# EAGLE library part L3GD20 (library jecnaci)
L3GD20 MEMS motion sensor - three-axis digital output gyroscope

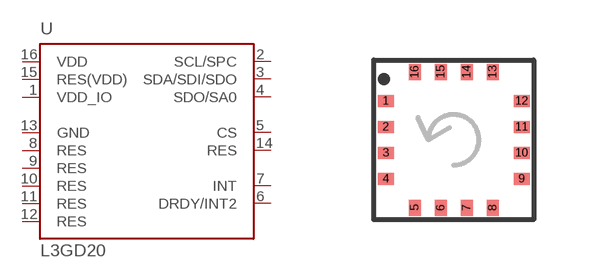
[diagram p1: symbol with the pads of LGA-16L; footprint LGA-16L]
Designator prefix U

## L3GD20  [LGA-16L]
1  VDD_IO  pwr
2  SCL/SPC  in
3  SDA/SDI/SDO
4  SDO/SA0  out
5  CS  in
6  DRDY/INT2
7  INT  out
8  RES  nc
9  RES  nc
10  RES  nc
11  RES  nc
12  RES  nc
13  GND  pwr
14  RES  nc
15  RES(VDD)  pwr
16  VDD  pwr

## Footprint LGA-16L (pad centres in mm)
smd 0.4 x 0.3: 1 -1.7,0.975; 2 -1.7,0.325; 3 -1.7,-0.325; 4 -1.7,-0.975; 9 1.7,-0.975; 10 1.7,-0.325; 11 1.7,0.325; 12 1.7,0.975
smd 0.3 x 0.4: 5 -0.975,-1.7; 6 -0.325,-1.7; 7 0.325,-1.7; 8 0.975,-1.7; 13 0.975,1.7; 14 0.325,1.7; 15 -0.325,1.7; 16 -0.975,1.7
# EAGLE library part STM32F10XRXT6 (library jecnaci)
STM32F101/103 64pin LQFP

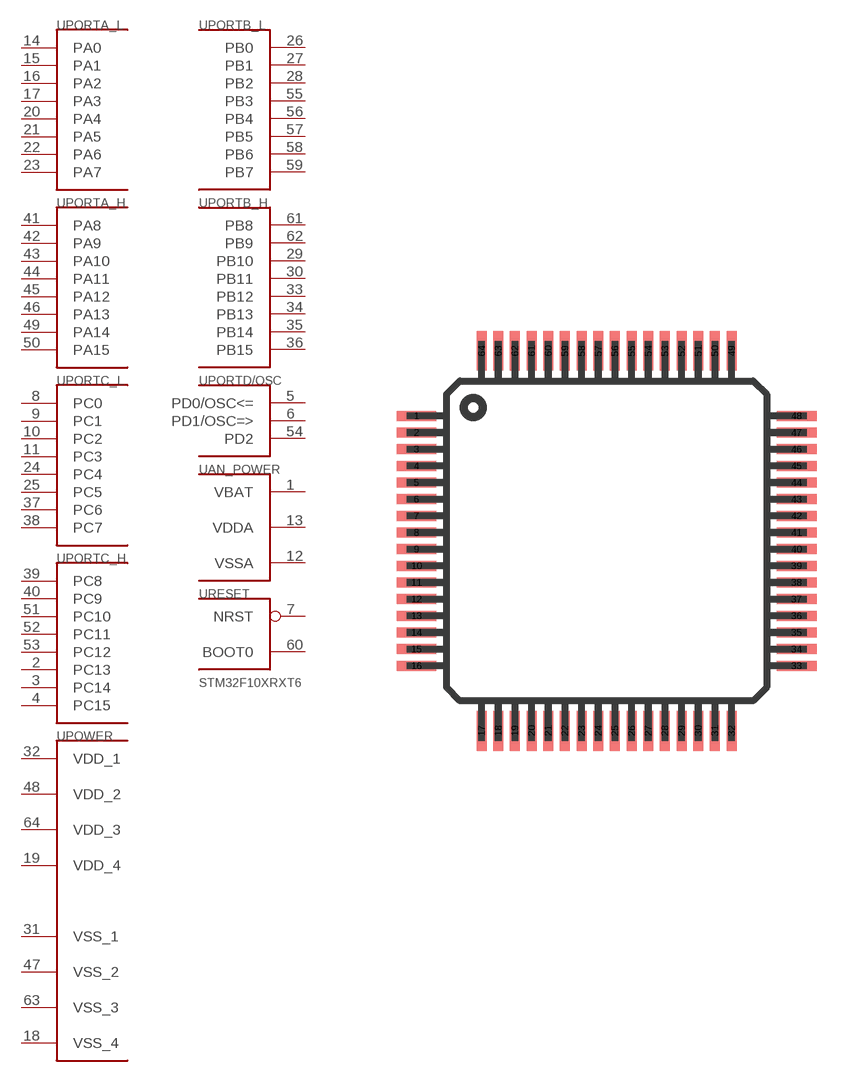
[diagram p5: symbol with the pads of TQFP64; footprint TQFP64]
Designator prefix U; gates PORTA_L=PORT_A_L PORTA_H=PORT_A_H PORTB_L=PORT_B_L PORTB_H=PORT_B_H PORTC_L=PORT_C_L PORTC_H=PORT_C_H POWER=VCC_VDD_M PORTD/OSC=PORT_D_3 AN_POWER=BAT_AN_M RESET=BOOT_RST

## STM32F10XRXT6  [TQFP64]
1  AN_POWER:VBAT  pwr
2  PORTC_H:PC13
3  PORTC_H:PC14
4  PORTC_H:PC15
5  PORTD/OSC:PD0/OSC<=
6  PORTD/OSC:PD1/OSC=>
7  RESET:NRST  in
8  PORTC_L:PC0
9  PORTC_L:PC1
10  PORTC_L:PC2
11  PORTC_L:PC3
12  AN_POWER:VSSA  pwr
13  AN_POWER:VDDA  pwr
14  PORTA_L:PA0
15  PORTA_L:PA1
16  PORTA_L:PA2
17  PORTA_L:PA3
18  POWER:VSS_4  pwr
19  POWER:VDD_4  pwr
20  PORTA_L:PA4
21  PORTA_L:PA5
22  PORTA_L:PA6
23  PORTA_L:PA7
24  PORTC_L:PC4
25  PORTC_L:PC5
26  PORTB_L:PB0
27  PORTB_L:PB1
28  PORTB_L:PB2
29  PORTB_H:PB10
30  PORTB_H:PB11
31  POWER:VSS_1  pwr
32  POWER:VDD_1  pwr
33  PORTB_H:PB12
34  PORTB_H:PB13
35  PORTB_H:PB14
36  PORTB_H:PB15
37  PORTC_L:PC6
38  PORTC_L:PC7
39  PORTC_H:PC8
40  PORTC_H:PC9
41  PORTA_H:PA8
42  PORTA_H:PA9
43  PORTA_H:PA10
44  PORTA_H:PA11
45  PORTA_H:PA12
46  PORTA_H:PA13
47  POWER:VSS_2  pwr
48  POWER:VDD_2  pwr
49  PORTA_H:PA14
50  PORTA_H:PA15
51  PORTC_H:PC10
52  PORTC_H:PC11
53  PORTC_H:PC12
54  PORTD/OSC:PD2
55  PORTB_L:PB3
56  PORTB_L:PB4
57  PORTB_L:PB5
58  PORTB_L:PB6
59  PORTB_L:PB7
60  RESET:BOOT0  in
61  PORTB_H:PB8
62  PORTB_H:PB9
63  POWER:VSS_3  pwr
64  POWER:VDD_3  pwr

## Footprint TQFP64 (pad centres in mm)
smd 1.2 x 0.3: 1 -5.7,3.75; 2 -5.7,3.25; 3 -5.7,2.75; 4 -5.7,2.25; 5 -5.7,1.75; 6 -5.7,1.25; 7 -5.7,0.75; 8 -5.7,0.25; 9 -5.7,-0.25; 10 -5.7,-0.75; 11 -5.7,-1.25; 12 -5.7,-1.75; 13 -5.7,-2.25; 14 -5.7,-2.75; 15 -5.7,-3.25; 16 -5.7,-3.75; 33 5.7,-3.75; 34 5.7,-3.25; 35 5.7,-2.75; 36 5.7,-2.25; 37 5.7,-1.75; 38 5.7,-1.25; 39 5.7,-0.75; 40 5.7,-0.25; 41 5.7,0.25; 42 5.7,0.75; 43 5.7,1.25; 44 5.7,1.75; 45 5.7,2.25; 46 5.7,2.75; 47 5.7,3.25; 48 5.7,3.75
smd 0.3 x 1.2: 17 -3.75,-5.7; 18 -3.25,-5.7; 19 -2.75,-5.7; 20 -2.25,-5.7; 21 -1.75,-5.7; 22 -1.25,-5.7; 23 -0.75,-5.7; 24 -0.25,-5.7; 25 0.25,-5.7; 26 0.75,-5.7; 27 1.25,-5.7; 28 1.75,-5.7; 29 2.25,-5.7; 30 2.75,-5.7; 31 3.25,-5.7; 32 3.75,-5.7; 49 3.75,5.7; 50 3.25,5.7; 51 2.75,5.7; 52 2.25,5.7; 53 1.75,5.7; 54 1.25,5.7; 55 0.75,5.7; 56 0.25,5.7; 57 -0.25,5.7; 58 -0.75,5.7; 59 -1.25,5.7; 60 -1.75,5.7; 61 -2.25,5.7; 62 -2.75,5.7; 63 -3.25,5.7; 64 -3.75,5.7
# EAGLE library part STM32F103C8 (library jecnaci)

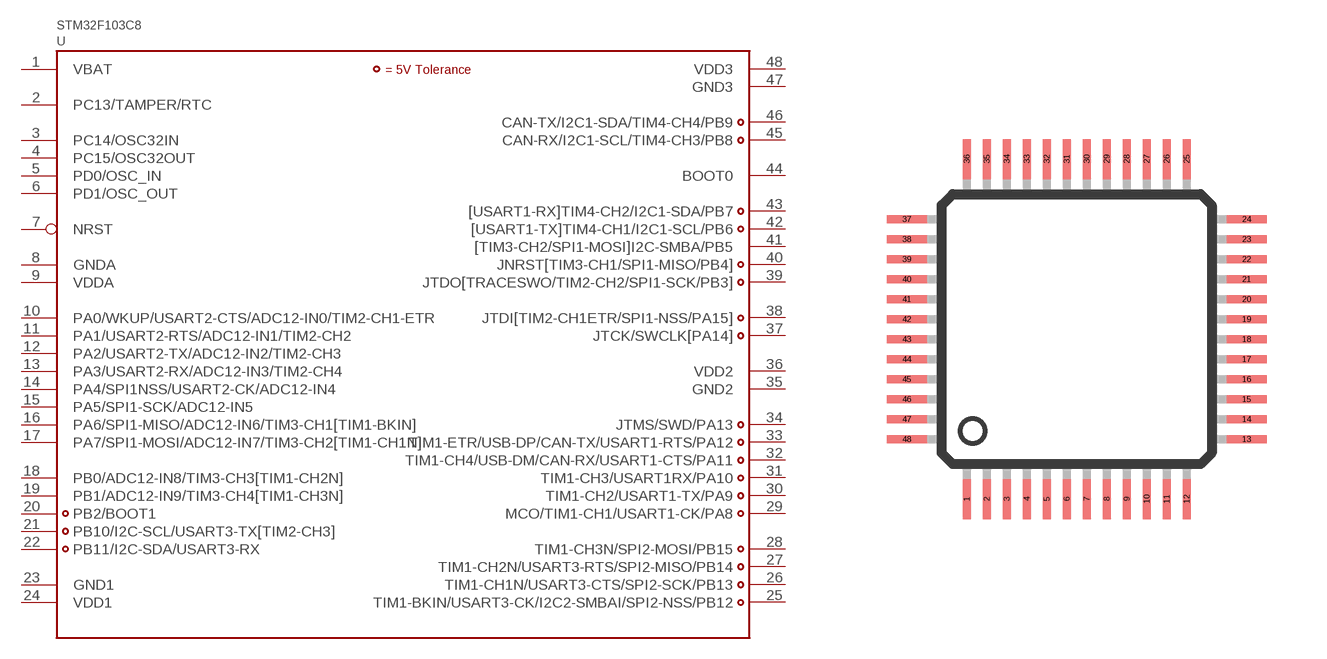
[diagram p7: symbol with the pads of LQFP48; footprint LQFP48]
Designator prefix U

## STM32F103C8LQFP48  [LQFP48]
1  VBAT  sup
2  PC13/TAMPER/RTC
3  PC14/OSC32IN
4  PC15/OSC32OUT
5  PD0/OSC_IN
6  PD1/OSC_OUT
7  NRST
8  GNDA  sup
9  VDDA  sup
10  PA0/WKUP/USART2-CTS/ADC12-IN0/TIM2-CH1-ETR
11  PA1/USART2-RTS/ADC12-IN1/TIM2-CH2
12  PA2/USART2-TX/ADC12-IN2/TIM2-CH3
13  PA3/USART2-RX/ADC12-IN3/TIM2-CH4
14  PA4/SPI1NSS/USART2-CK/ADC12-IN4
15  PA5/SPI1-SCK/ADC12-IN5
16  PA6/SPI1-MISO/ADC12-IN6/TIM3-CH1[TIM1-BKIN]
17  PA7/SPI1-MOSI/ADC12-IN7/TIM3-CH2[TIM1-CH1N]
18  PB0/ADC12-IN8/TIM3-CH3[TIM1-CH2N]
19  PB1/ADC12-IN9/TIM3-CH4[TIM1-CH3N]
20  PB2/BOOT1
21  PB10/I2C-SCL/USART3-TX[TIM2-CH3]
22  PB11/I2C-SDA/USART3-RX
23  GND1  sup
24  VDD1  sup
25  TIM1-BKIN/USART3-CK/I2C2-SMBAI/SPI2-NSS/PB12
26  TIM1-CH1N/USART3-CTS/SPI2-SCK/PB13
27  TIM1-CH2N/USART3-RTS/SPI2-MISO/PB14
28  TIM1-CH3N/SPI2-MOSI/PB15
29  MCO/TIM1-CH1/USART1-CK/PA8
30  TIM1-CH2/USART1-TX/PA9
31  TIM1-CH3/USART1RX/PA10
32  TIM1-CH4/USB-DM/CAN-RX/USART1-CTS/PA11
33  TIM1-ETR/USB-DP/CAN-TX/USART1-RTS/PA12
34  JTMS/SWD/PA13
35  GND2  sup
36  VDD2  sup
37  JTCK/SWCLK[PA14]
38  JTDI[TIM2-CH1ETR/SPI1-NSS/PA15]
39  JTDO[TRACESWO/TIM2-CH2/SPI1-SCK/PB3]
40  JNRST[TIM3-CH1/SPI1-MISO/PB4]
41  [TIM3-CH2/SPI1-MOSI]I2C-SMBA/PB5
42  [USART1-TX]TIM4-CH1/I2C1-SCL/PB6
43  [USART1-RX]TIM4-CH2/I2C1-SDA/PB7
44  BOOT0
45  CAN-RX/I2C1-SCL/TIM4-CH3/PB8
46  CAN-TX/I2C1-SDA/TIM4-CH4/PB9
47  GND3  sup
48  VDD3  sup

## Footprint LQFP48 (pad centres in mm)
48-pin plastic LQFP (FPT-48P-M26) www.fma.fujitsu.com/pdf/e713717.pdf
smd 0.2 x 1: 1 -2.75,-4.25; 2 -2.25,-4.25; 3 -1.75,-4.25; 4 -1.25,-4.25; 5 -0.75,-4.25; 6 -0.25,-4.25; 7 0.25,-4.25; 8 0.75,-4.25; 9 1.25,-4.25; 10 1.75,-4.25; 11 2.25,-4.25; 12 2.75,-4.25; 25 2.75,4.25; 26 2.25,4.25; 27 1.75,4.25; 28 1.25,4.25; 29 0.75,4.25; 30 0.25,4.25; 31 -0.25,4.25; 32 -0.75,4.25; 33 -1.25,4.25; 34 -1.75,4.25; 35 -2.25,4.25; 36 -2.75,4.25
smd 1 x 0.2: 13 4.25,-2.75; 14 4.25,-2.25; 15 4.25,-1.75; 16 4.25,-1.25; 17 4.25,-0.75; 18 4.25,-0.25; 19 4.25,0.25; 20 4.25,0.75; 21 4.25,1.25; 22 4.25,1.75; 23 4.25,2.25; 24 4.25,2.75; 37 -4.25,2.75; 38 -4.25,2.25; 39 -4.25,1.75; 40 -4.25,1.25; 41 -4.25,0.75; 42 -4.25,0.25; 43 -4.25,-0.25; 44 -4.25,-0.75; 45 -4.25,-1.25; 46 -4.25,-1.75; 47 -4.25,-2.25; 48 -4.25,-2.75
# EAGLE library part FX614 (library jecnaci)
FX614 Bell 202 Compatible Modem Features 1200bits/sec 1/2 Duplex Bell 202 compatible Modem with: · Optional 5bits/sec and 150bits/sec Back Channel · Optional 1200bits/sec Data Retiming Facility · 3.0 to 5.5V Supply; 1.0mA at 3V 'Zero-Power' Mode; 1mA · Optional Line Equalisation · -40°C to +85°C Operating Temperature · 16-pin SOIC and DIL Packages · 3.58MHz Xtal/Clock Rate Brief Description The FX614 is a low power CMOS integrated circuit for the reception or transmission of asynchronous 1200bits/sec data and is suitable for use in Bell 202 type systems. It is also capable of generating the 5bits/sec or 150bits/sec 'back channel'. The device incorporates an optional Tx and Rx data retiming function that removes the need for a UART in the associated mC when operating at 1200bits/sec. An optional line equaliser is incorporated into the receive path, this is controlled by an external logic level. The FX614 may be used in a wide range of telephone telemetry systems. With a low operating voltage of 3.0V, a very low current 'sleep' mode (1mA) and an operating current of 1mA the device is ideal for portable, terminal and line powered applications. A 3.58MHz standard Xtal/Clock rate is required and the device operates from a 3.0V to 5.5V supply. Both SOIC (D4) and Plastic DIL (P3) 16-pin package types are available. Contact CONSUMER MICROCIRCUITS LIMITED Telephone: +44 1376 513833 Telefax: +44 1376 518247 ENGLAND e-mail: sales@cmlmicro.co.uk http://www.cmlmicro.co.uk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

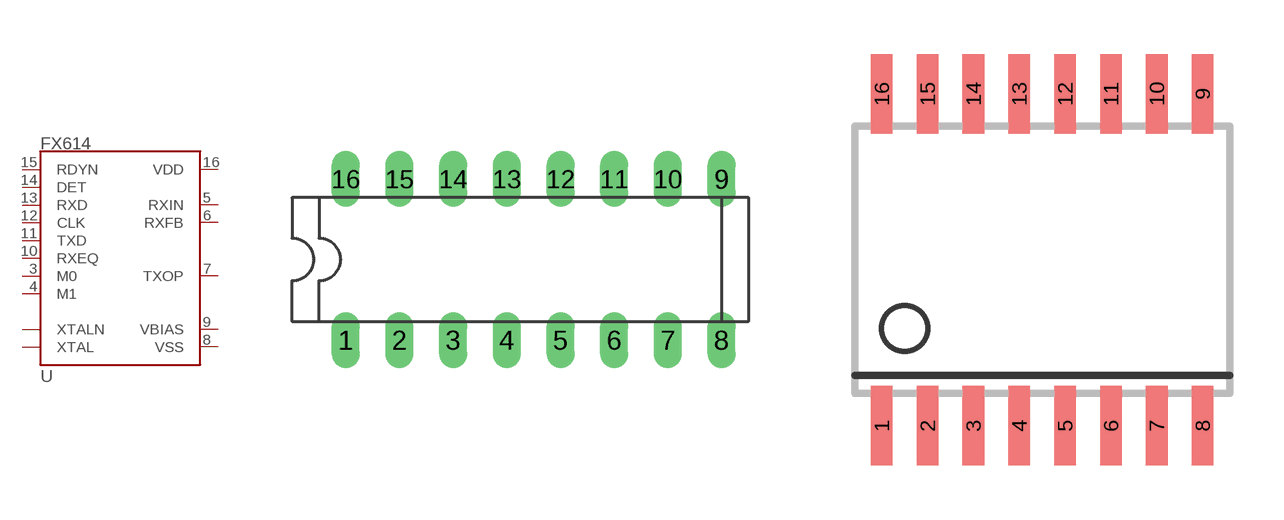
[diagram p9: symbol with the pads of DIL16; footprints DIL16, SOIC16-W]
Designator prefix -

## FX614DIL  [DIL16]
1  XTALN  oc
2  XTAL  oc
3  M0  in
4  M1  in
5  RXIN  in
6  RXFB  out
7  TXOP  out
8  VSS  pwr
9  VBIAS  pwr
10  RXEQ  in
11  TXD  in
12  CLK  in
13  RXD  out
14  DET  out
15  RDYN  out
16  VDD  pwr

## FX614SOIC  [SOIC16-W]
Pads as for DIL16

## Footprint DIL16 (pad centres in mm)
Dual In Line Package
drill 0.813 long: 1 -7.62,-3.81; 2 -5.08,-3.81; 3 -2.54,-3.81; 4 0,-3.81; 5 2.54,-3.81; 6 5.08,-3.81; 7 7.62,-3.81; 8 10.16,-3.81; 9 10.16,3.81; 10 7.62,3.81; 11 5.08,3.81; 12 2.54,3.81; 13 0,3.81; 14 -2.54,3.81; 15 -5.08,3.81; 16 -7.62,3.81

## Footprint SOIC16-W (pad centres in mm)
16-pin SOIC (D4)
smd 0.6 x 2.2: 1 -3.81,-4.6; 2 -2.54,-4.6; 3 -1.27,-4.6; 4 0,-4.6; 5 1.27,-4.6; 6 2.54,-4.6; 7 3.81,-4.6; 8 5.08,-4.6; 9 5.08,4.6; 10 3.81,4.6; 11 2.54,4.6; 12 1.27,4.6; 13 0,4.6; 14 -1.27,4.6; 15 -2.54,4.6; 16 -3.81,4.6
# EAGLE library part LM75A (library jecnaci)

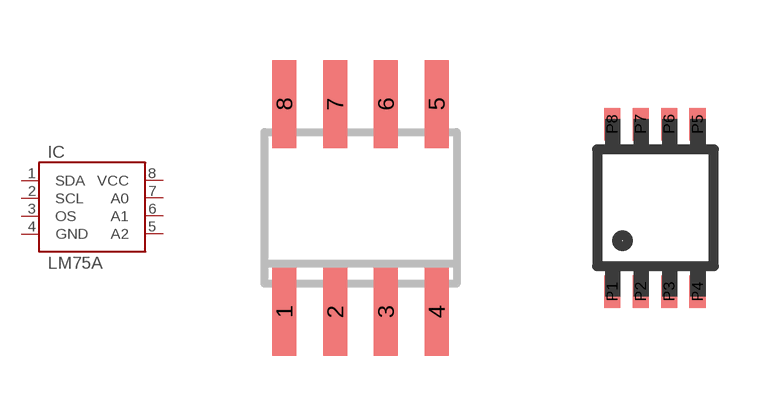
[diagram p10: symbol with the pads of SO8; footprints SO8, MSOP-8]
Designator prefix IC

## LM75A  [SO8]
1  SDA
2  SCL
3  OS
4  GND
5  A2
6  A1
7  A0
8  VCC

## LM75AMSOP8  [MSOP-8]
P1  SDA
P2  SCL
P3  OS
P4  GND
P5  A2
P6  A1
P7  A0
P8  VCC

## Footprint SO8 (pad centres in mm)
smd 0.6 x 2.2: 1 -1.905,-2.6; 2 -0.635,-2.6; 3 0.635,-2.6; 4 1.905,-2.6; 5 1.905,2.6; 6 0.635,2.6; 7 -0.635,2.6; 8 -1.905,2.6

## Footprint MSOP-8 (pad centres in mm)
Small Outline Package SO-8, CASE 751
smd 0.406 x 0.813: P1 -2.159,-2.54; P2 -1.448,-2.54; P3 -0.737,-2.54; P4 -0.025,-2.54; P5 -0.025,1.651; P6 -0.737,1.651; P7 -1.448,1.651; P8 -2.159,1.651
